VERSION 5.8 ;
BUSBITCHARS "[]" ;
DIVIDERCHAR "/" ;

SITE  CoreSite2
    CLASS       CORE ;
    SYMMETRY    Y ;
    SIZE        0.48 BY 7.56 ;
END  CoreSite2

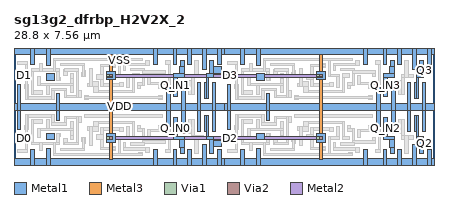
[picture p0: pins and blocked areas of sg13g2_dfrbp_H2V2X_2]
MACRO sg13g2_dfrbp_H2V2X_2
  CLASS CORE ;
  ORIGIN 0 0 ;
  FOREIGN sg13g2_dfrbp_H2V2X_2 0 0 ;
  SIZE 28.800 BY 7.560 ;
  SYMMETRY X Y ;
  SITE CoreSite2 ;
  PIN D0
    DIRECTION INPUT ;
    USE SIGNAL ;
    ANTENNAMODEL OXIDE1 ;
    ANTENNAGATEAREA 0.1092 LAYER Metal1 ;
    PORT
      LAYER Metal1 ;
        RECT 0.255 1.375 0.610 1.855 ;
    END
  END D0
  PIN Q0
    DIRECTION OUTPUT ;
    USE SIGNAL ;
    ANTENNADIFFAREA 0.7124 LAYER Metal1 ;
    PORT
      LAYER Metal1 ;
        RECT 13.440 0.595 13.700 1.775 ;
        RECT 13.440 1.045 14.210 1.490 ;
    END
    PORT
      LAYER Metal1 ;
        RECT 13.190 1.515 13.700 1.775 ;
        RECT 13.190 1.515 13.360 3.175 ;
        RECT 13.065 2.085 13.360 3.175 ;
    END
  END Q0
  PIN Q_N0
    DIRECTION OUTPUT ;
    USE SIGNAL ;
    ANTENNADIFFAREA 0.7068 LAYER Metal1 ;
    PORT
      LAYER Metal1 ;
        RECT 11.395 0.590 11.660 1.740 ;
        RECT 11.340 0.990 11.720 1.740 ;
        RECT 10.960 1.520 11.720 1.740 ;
        RECT 10.960 1.520 11.220 3.060 ;
    END
  END Q_N0
  PIN D1
    DIRECTION INPUT ;
    USE SIGNAL ;
    ANTENNAMODEL OXIDE1 ;
    ANTENNAGATEAREA 0.1092 LAYER Metal1 ;
    PORT
      LAYER Metal1 ;
        RECT 0.255 5.705 0.610 6.185 ;
    END
  END D1
  PIN Q1
    DIRECTION OUTPUT ;
    USE SIGNAL ;
    ANTENNADIFFAREA 0.7124 LAYER Metal1 ;
    PORT
      LAYER Metal1 ;
        RECT 13.065 4.385 13.360 5.475 ;
        RECT 13.190 4.385 13.360 6.045 ;
        RECT 13.190 5.785 13.700 6.045 ;
    END
    PORT
      LAYER Metal1 ;
        RECT 13.440 6.070 14.210 6.515 ;
        RECT 13.440 5.785 13.700 6.965 ;
    END
  END Q1
  PIN Q_N1
    DIRECTION OUTPUT ;
    USE SIGNAL ;
    ANTENNADIFFAREA 0.7068 LAYER Metal1 ;
    PORT
      LAYER Metal1 ;
        RECT 10.960 4.500 11.220 6.040 ;
        RECT 10.960 5.820 11.720 6.040 ;
        RECT 11.340 5.820 11.720 6.570 ;
        RECT 11.395 5.820 11.660 6.970 ;
    END
  END Q_N1
  PIN D2
    DIRECTION INPUT ;
    USE SIGNAL ;
    ANTENNAMODEL OXIDE1 ;
    ANTENNAGATEAREA 0.1092 LAYER Metal1 ;
    PORT
      LAYER Metal1 ;
        RECT 14.655 1.375 15.010 1.855 ;
    END
  END D2
  PIN Q2
    DIRECTION OUTPUT ;
    USE SIGNAL ;
    ANTENNADIFFAREA 0.7124 LAYER Metal1 ;
    PORT
      LAYER Metal1 ;
        RECT 27.840 0.595 28.100 1.775 ;
        RECT 27.840 1.045 28.610 1.490 ;
    END
    PORT
      LAYER Metal1 ;
        RECT 27.590 1.515 28.100 1.775 ;
        RECT 27.590 1.515 27.760 3.175 ;
        RECT 27.465 2.085 27.760 3.175 ;
    END
  END Q2
  PIN Q_N2
    DIRECTION OUTPUT ;
    USE SIGNAL ;
    ANTENNADIFFAREA 0.7068 LAYER Metal1 ;
    PORT
      LAYER Metal1 ;
        RECT 25.795 0.590 26.060 1.740 ;
        RECT 25.740 0.990 26.120 1.740 ;
        RECT 25.360 1.520 26.120 1.740 ;
        RECT 25.360 1.520 25.620 3.060 ;
    END
  END Q_N2
  PIN D3
    DIRECTION INPUT ;
    USE SIGNAL ;
    ANTENNAMODEL OXIDE1 ;
    ANTENNAGATEAREA 0.1092 LAYER Metal1 ;
    PORT
      LAYER Metal1 ;
        RECT 14.655 5.705 15.010 6.185 ;
    END
  END D3
  PIN Q3
    DIRECTION OUTPUT ;
    USE SIGNAL ;
    ANTENNADIFFAREA 0.7124 LAYER Metal1 ;
    PORT
      LAYER Metal1 ;
        RECT 27.465 4.385 27.760 5.475 ;
        RECT 27.590 4.385 27.760 6.045 ;
        RECT 27.590 5.785 28.100 6.045 ;
    END
    PORT
      LAYER Metal1 ;
        RECT 27.840 6.070 28.610 6.515 ;
        RECT 27.840 5.785 28.100 6.965 ;
    END
  END Q3
  PIN Q_N3
    DIRECTION OUTPUT ;
    USE SIGNAL ;
    ANTENNADIFFAREA 0.7068 LAYER Metal1 ;
    PORT
      LAYER Metal1 ;
        RECT 25.360 4.500 25.620 6.040 ;
        RECT 25.360 5.820 26.120 6.040 ;
        RECT 25.740 5.820 26.120 6.570 ;
        RECT 25.795 5.820 26.060 6.970 ;
    END
  END Q_N3
  PIN VDD
    DIRECTION INOUT ;
    USE POWER ;
    SHAPE ABUTMENT ;
    NETEXPR "VDD VDD!" ;
    PORT
      LAYER Metal1 ;
        RECT 11.470 1.980 11.730 4.000 ;
        RECT 25.870 1.980 26.130 4.000 ;
        RECT 13.580 2.085 13.840 4.000 ;
        RECT 12.555 2.085 12.815 4.000 ;
        RECT 27.980 2.085 28.240 4.000 ;
        RECT 26.955 2.085 27.215 4.000 ;
        RECT 0.215 2.215 0.470 4.000 ;
        RECT 14.615 2.215 14.870 4.000 ;
        RECT 10.450 2.460 10.710 4.000 ;
        RECT 24.850 2.460 25.110 4.000 ;
        RECT 2.945 2.860 3.115 4.000 ;
        RECT 17.345 2.860 17.515 4.000 ;
        RECT 0.000 3.560 14.400 4.000 ;
        RECT 14.400 3.560 28.800 4.000 ;
        RECT 2.945 3.560 3.115 4.700 ;
        RECT 17.345 3.560 17.515 4.700 ;
        RECT 10.450 3.560 10.710 5.100 ;
        RECT 24.850 3.560 25.110 5.100 ;
        RECT 0.215 3.560 0.470 5.345 ;
        RECT 14.615 3.560 14.870 5.345 ;
        RECT 13.580 3.560 13.840 5.475 ;
        RECT 12.555 3.560 12.815 5.475 ;
        RECT 27.980 3.560 28.240 5.475 ;
        RECT 26.955 3.560 27.215 5.475 ;
        RECT 11.470 3.560 11.730 5.580 ;
        RECT 25.870 3.560 26.130 5.580 ;
    END
  END VDD
  PIN VSS
    DIRECTION INOUT ;
    USE GROUND ;
    SHAPE ABUTMENT ;
    NETEXPR "VSS VSS!" ;
    PORT
      LAYER Metal1 ;
        RECT 0.000 -0.220 14.400 0.220 ;
        RECT 14.400 -0.220 28.800 0.220 ;
        RECT 13.935 -0.220 14.210 0.840 ;
        RECT 28.335 -0.220 28.610 0.840 ;
        RECT 11.910 -0.220 12.170 0.850 ;
        RECT 10.910 -0.220 11.150 0.850 ;
        RECT 26.310 -0.220 26.570 0.850 ;
        RECT 25.310 -0.220 25.550 0.850 ;
        RECT 9.560 -0.220 9.820 0.885 ;
        RECT 1.140 -0.220 1.400 0.885 ;
        RECT 23.960 -0.220 24.220 0.885 ;
        RECT 15.540 -0.220 15.800 0.885 ;
        RECT 2.235 -0.220 2.495 0.915 ;
        RECT 16.635 -0.220 16.895 0.915 ;
        RECT 12.930 -0.220 13.190 1.210 ;
        RECT 27.330 -0.220 27.590 1.210 ;
    END
    PORT
      LAYER Metal1 ;
        RECT 12.930 6.350 13.190 7.780 ;
        RECT 27.330 6.350 27.590 7.780 ;
        RECT 2.235 6.645 2.495 7.780 ;
        RECT 16.635 6.645 16.895 7.780 ;
        RECT 9.560 6.675 9.820 7.780 ;
        RECT 1.140 6.675 1.400 7.780 ;
        RECT 23.960 6.675 24.220 7.780 ;
        RECT 15.540 6.675 15.800 7.780 ;
        RECT 11.910 6.710 12.170 7.780 ;
        RECT 10.910 6.710 11.150 7.780 ;
        RECT 26.310 6.710 26.570 7.780 ;
        RECT 25.310 6.710 25.550 7.780 ;
        RECT 13.935 6.720 14.210 7.780 ;
        RECT 28.335 6.720 28.610 7.780 ;
        RECT 0.000 7.340 14.400 7.780 ;
        RECT 14.400 7.340 28.800 7.780 ;
    END
  END VSS
  PIN CLK
    DIRECTION INPUT ;
    USE SIGNAL ;
    ANTENNAMODEL OXIDE1 ;
    ANTENNAGATEAREA 0.2418 LAYER Metal1 ;
    PORT
      LAYER Metal1 ;
        RECT 6.365 1.335 6.990 1.935 ;
        RECT 6.365 5.625 6.990 6.225 ;
        RECT 20.765 1.335 21.390 1.935 ;
        RECT 20.765 5.625 21.390 6.225 ;
      LAYER Metal3 ;
        RECT 6.580 0.200 6.780 7.360 ;
      LAYER Via1 ;
        RECT 6.365 1.540 6.555 1.730 ;
      LAYER Via2 ;
        RECT 6.580 1.540 6.770 1.730 ;
      LAYER Metal2 ;
        RECT 6.360 1.535 6.775 1.735 ;
      LAYER Via1 ;
        RECT 6.365 5.830 6.555 6.020 ;
      LAYER Via2 ;
        RECT 6.580 5.830 6.770 6.020 ;
      LAYER Metal2 ;
        RECT 6.360 5.825 6.775 6.025 ;
      LAYER Metal3 ;
        RECT 20.980 0.200 21.180 7.360 ;
      LAYER Via1 ;
        RECT 20.765 1.540 20.955 1.730 ;
      LAYER Via2 ;
        RECT 20.980 1.540 21.170 1.730 ;
      LAYER Metal2 ;
        RECT 20.760 1.535 21.175 1.735 ;
      LAYER Via1 ;
        RECT 20.765 5.830 20.955 6.020 ;
      LAYER Via2 ;
        RECT 20.980 5.830 21.170 6.020 ;
      LAYER Metal2 ;
        RECT 20.760 5.825 21.175 6.025 ;
        RECT 6.360 1.535 21.175 1.735 ;
        RECT 6.360 5.825 21.175 6.025 ;
    END
  END CLK
  PIN RESET_B
    DIRECTION INPUT ;
    USE SIGNAL ;
    ANTENNAPARTIALMETALAREA 0.905 LAYER Metal1 ;
    ANTENNAMODEL OXIDE1 ;
    ANTENNAGATEAREA 0.3276 LAYER Metal1 ;
    ANTENNAMAXAREACAR 2.762515 LAYER Metal1 ;
    PORT
      LAYER Metal1 ;
        RECT 2.200 1.510 2.750 1.965 ;
        RECT 16.600 1.510 17.150 1.965 ;
    END
    PORT
      LAYER Metal1 ;
        RECT 2.200 5.595 2.750 6.050 ;
        RECT 16.600 5.595 17.150 6.050 ;
    END
  END RESET_B
  OBS
    LAYER Metal1 ;
      RECT 11.980 1.980 12.360 2.920 ;
      RECT 12.190 1.535 12.360 2.920 ;
      RECT 12.190 1.535 12.985 1.795 ;
      RECT 12.400 0.590 12.685 1.795 ;
      RECT 9.910 2.100 10.170 2.495 ;
      RECT 9.130 2.100 10.730 2.260 ;
      RECT 10.570 0.625 10.730 2.260 ;
      RECT 9.130 1.655 9.385 2.260 ;
      RECT 10.380 0.625 10.730 0.885 ;
      RECT 8.455 2.125 8.660 2.500 ;
      RECT 8.455 2.125 8.950 2.295 ;
      RECT 8.790 1.145 8.950 2.295 ;
      RECT 10.165 1.275 10.390 1.665 ;
      RECT 8.790 1.275 10.390 1.465 ;
      RECT 7.960 1.145 8.970 1.315 ;
      RECT 9.910 3.025 10.180 3.285 ;
      RECT 4.855 3.025 5.115 3.285 ;
      RECT 4.855 3.075 10.180 3.235 ;
      RECT 7.510 0.805 7.680 1.310 ;
      RECT 7.510 0.805 9.310 0.965 ;
      RECT 9.050 0.625 9.310 0.965 ;
      RECT 1.200 2.640 1.940 2.900 ;
      RECT 1.200 1.170 1.360 2.900 ;
      RECT 7.745 1.555 7.935 2.450 ;
      RECT 2.935 1.755 3.215 1.965 ;
      RECT 2.935 1.170 3.095 1.965 ;
      RECT 7.170 1.555 7.935 1.725 ;
      RECT 7.170 0.440 7.330 1.725 ;
      RECT 1.200 1.170 3.095 1.330 ;
      RECT 2.705 0.440 2.875 1.330 ;
      RECT 1.720 0.815 1.980 1.330 ;
      RECT 8.540 0.440 8.800 0.625 ;
      RECT 2.705 0.440 8.800 0.605 ;
      RECT 5.425 2.630 8.275 2.790 ;
      RECT 8.115 1.510 8.275 2.790 ;
      RECT 5.425 2.060 5.785 2.790 ;
      RECT 5.020 2.150 5.785 2.410 ;
      RECT 5.155 2.060 5.785 2.410 ;
      RECT 5.155 1.135 5.415 2.410 ;
      RECT 8.115 1.510 8.600 1.770 ;
      RECT 5.965 2.145 7.525 2.370 ;
      RECT 7.265 2.075 7.525 2.370 ;
      RECT 5.965 0.855 6.125 2.370 ;
      RECT 5.650 1.540 6.125 1.870 ;
      RECT 6.755 0.810 6.990 1.070 ;
      RECT 5.965 0.855 6.990 1.025 ;
      RECT 4.630 1.440 4.895 1.700 ;
      RECT 4.685 1.300 4.895 1.700 ;
      RECT 4.685 0.785 4.865 1.700 ;
      RECT 3.165 0.785 4.865 0.960 ;
      RECT 0.790 3.080 2.765 3.240 ;
      RECT 2.605 2.520 2.765 3.240 ;
      RECT 3.455 2.985 4.625 3.145 ;
      RECT 4.290 2.685 4.625 3.145 ;
      RECT 0.790 2.240 0.980 3.240 ;
      RECT 3.455 2.520 3.615 3.145 ;
      RECT 4.290 1.170 4.450 3.145 ;
      RECT 2.605 2.520 3.615 2.680 ;
      RECT 0.720 2.240 0.980 2.520 ;
      RECT 0.790 0.645 0.950 3.240 ;
      RECT 3.385 1.225 3.645 1.640 ;
      RECT 3.465 1.170 4.450 1.330 ;
      RECT 0.210 0.645 0.950 0.840 ;
      RECT 2.245 2.145 2.425 2.900 ;
      RECT 3.890 1.510 4.075 2.805 ;
      RECT 2.245 2.145 4.075 2.315 ;
      RECT 1.585 2.145 4.075 2.305 ;
      RECT 1.585 1.705 1.845 2.305 ;
      RECT 3.890 1.510 4.110 1.810 ;
      RECT 11.980 4.640 12.360 5.580 ;
      RECT 12.190 4.640 12.360 6.025 ;
      RECT 12.190 5.765 12.985 6.025 ;
      RECT 12.400 5.765 12.685 6.970 ;
      RECT 9.910 5.065 10.170 5.460 ;
      RECT 9.130 5.300 10.730 5.460 ;
      RECT 10.570 5.300 10.730 6.935 ;
      RECT 9.130 5.300 9.385 5.905 ;
      RECT 10.380 6.675 10.730 6.935 ;
      RECT 8.455 5.060 8.660 5.435 ;
      RECT 8.455 5.265 8.950 5.435 ;
      RECT 8.790 5.265 8.950 6.415 ;
      RECT 10.165 5.895 10.390 6.285 ;
      RECT 8.790 6.095 10.390 6.285 ;
      RECT 7.960 6.245 8.970 6.415 ;
      RECT 9.910 4.275 10.180 4.535 ;
      RECT 4.855 4.275 5.115 4.535 ;
      RECT 4.855 4.325 10.180 4.485 ;
      RECT 7.510 6.250 7.680 6.755 ;
      RECT 7.510 6.595 9.310 6.755 ;
      RECT 9.050 6.595 9.310 6.935 ;
      RECT 1.200 4.660 1.940 4.920 ;
      RECT 1.200 4.660 1.360 6.390 ;
      RECT 7.745 5.110 7.935 6.005 ;
      RECT 2.935 5.595 3.215 5.805 ;
      RECT 2.935 5.595 3.095 6.390 ;
      RECT 7.170 5.835 7.935 6.005 ;
      RECT 7.170 5.835 7.330 7.120 ;
      RECT 1.200 6.230 3.095 6.390 ;
      RECT 2.705 6.230 2.875 7.120 ;
      RECT 1.720 6.230 1.980 6.745 ;
      RECT 8.540 6.935 8.800 7.120 ;
      RECT 2.705 6.955 8.800 7.120 ;
      RECT 5.425 4.770 8.275 4.930 ;
      RECT 8.115 4.770 8.275 6.050 ;
      RECT 5.425 4.770 5.785 5.500 ;
      RECT 5.020 5.150 5.785 5.410 ;
      RECT 5.155 5.150 5.785 5.500 ;
      RECT 5.155 5.150 5.415 6.425 ;
      RECT 8.115 5.790 8.600 6.050 ;
      RECT 5.965 5.190 7.525 5.415 ;
      RECT 7.265 5.190 7.525 5.485 ;
      RECT 5.965 5.190 6.125 6.705 ;
      RECT 5.650 5.690 6.125 6.020 ;
      RECT 6.755 6.490 6.990 6.750 ;
      RECT 5.965 6.535 6.990 6.705 ;
      RECT 4.630 5.860 4.895 6.120 ;
      RECT 4.685 5.860 4.895 6.260 ;
      RECT 4.685 5.860 4.865 6.775 ;
      RECT 3.165 6.600 4.865 6.775 ;
      RECT 0.790 4.320 2.765 4.480 ;
      RECT 2.605 4.320 2.765 5.040 ;
      RECT 3.455 4.415 4.625 4.575 ;
      RECT 4.290 4.415 4.625 4.875 ;
      RECT 0.790 4.320 0.980 5.320 ;
      RECT 3.455 4.415 3.615 5.040 ;
      RECT 4.290 4.415 4.450 6.390 ;
      RECT 2.605 4.880 3.615 5.040 ;
      RECT 0.720 5.040 0.980 5.320 ;
      RECT 0.790 4.320 0.950 6.915 ;
      RECT 3.385 5.920 3.645 6.335 ;
      RECT 3.465 6.230 4.450 6.390 ;
      RECT 0.210 6.720 0.950 6.915 ;
      RECT 2.245 4.660 2.425 5.415 ;
      RECT 3.890 4.755 4.075 6.050 ;
      RECT 2.245 5.245 4.075 5.415 ;
      RECT 1.585 5.255 4.075 5.415 ;
      RECT 1.585 5.255 1.845 5.855 ;
      RECT 3.890 5.750 4.110 6.050 ;
      RECT 26.380 1.980 26.760 2.920 ;
      RECT 26.590 1.535 26.760 2.920 ;
      RECT 26.590 1.535 27.385 1.795 ;
      RECT 26.800 0.590 27.085 1.795 ;
      RECT 24.310 2.100 24.570 2.495 ;
      RECT 23.530 2.100 25.130 2.260 ;
      RECT 24.970 0.625 25.130 2.260 ;
      RECT 23.530 1.655 23.785 2.260 ;
      RECT 24.780 0.625 25.130 0.885 ;
      RECT 22.855 2.125 23.060 2.500 ;
      RECT 22.855 2.125 23.350 2.295 ;
      RECT 23.190 1.145 23.350 2.295 ;
      RECT 24.565 1.275 24.790 1.665 ;
      RECT 23.190 1.275 24.790 1.465 ;
      RECT 22.360 1.145 23.370 1.315 ;
      RECT 24.310 3.025 24.580 3.285 ;
      RECT 19.255 3.025 19.515 3.285 ;
      RECT 19.255 3.075 24.580 3.235 ;
      RECT 21.910 0.805 22.080 1.310 ;
      RECT 21.910 0.805 23.710 0.965 ;
      RECT 23.450 0.625 23.710 0.965 ;
      RECT 15.600 2.640 16.340 2.900 ;
      RECT 15.600 1.170 15.760 2.900 ;
      RECT 22.145 1.555 22.335 2.450 ;
      RECT 17.335 1.755 17.615 1.965 ;
      RECT 17.335 1.170 17.495 1.965 ;
      RECT 21.570 1.555 22.335 1.725 ;
      RECT 21.570 0.440 21.730 1.725 ;
      RECT 15.600 1.170 17.495 1.330 ;
      RECT 17.105 0.440 17.275 1.330 ;
      RECT 16.120 0.815 16.380 1.330 ;
      RECT 22.940 0.440 23.200 0.625 ;
      RECT 17.105 0.440 23.200 0.605 ;
      RECT 19.825 2.630 22.675 2.790 ;
      RECT 22.515 1.510 22.675 2.790 ;
      RECT 19.825 2.060 20.185 2.790 ;
      RECT 19.420 2.150 20.185 2.410 ;
      RECT 19.555 2.060 20.185 2.410 ;
      RECT 19.555 1.135 19.815 2.410 ;
      RECT 22.515 1.510 23.000 1.770 ;
      RECT 20.365 2.145 21.925 2.370 ;
      RECT 21.665 2.075 21.925 2.370 ;
      RECT 20.365 0.855 20.525 2.370 ;
      RECT 20.050 1.540 20.525 1.870 ;
      RECT 21.155 0.810 21.390 1.070 ;
      RECT 20.365 0.855 21.390 1.025 ;
      RECT 19.030 1.440 19.295 1.700 ;
      RECT 19.085 1.300 19.295 1.700 ;
      RECT 19.085 0.785 19.265 1.700 ;
      RECT 17.565 0.785 19.265 0.960 ;
      RECT 15.190 3.080 17.165 3.240 ;
      RECT 17.005 2.520 17.165 3.240 ;
      RECT 17.855 2.985 19.025 3.145 ;
      RECT 18.690 2.685 19.025 3.145 ;
      RECT 15.190 2.240 15.380 3.240 ;
      RECT 17.855 2.520 18.015 3.145 ;
      RECT 18.690 1.170 18.850 3.145 ;
      RECT 17.005 2.520 18.015 2.680 ;
      RECT 15.120 2.240 15.380 2.520 ;
      RECT 15.190 0.645 15.350 3.240 ;
      RECT 17.785 1.225 18.045 1.640 ;
      RECT 17.865 1.170 18.850 1.330 ;
      RECT 14.610 0.645 15.350 0.840 ;
      RECT 16.645 2.145 16.825 2.900 ;
      RECT 18.290 1.510 18.475 2.805 ;
      RECT 16.645 2.145 18.475 2.315 ;
      RECT 15.985 2.145 18.475 2.305 ;
      RECT 15.985 1.705 16.245 2.305 ;
      RECT 18.290 1.510 18.510 1.810 ;
      RECT 26.380 4.640 26.760 5.580 ;
      RECT 26.590 4.640 26.760 6.025 ;
      RECT 26.590 5.765 27.385 6.025 ;
      RECT 26.800 5.765 27.085 6.970 ;
      RECT 24.310 5.065 24.570 5.460 ;
      RECT 23.530 5.300 25.130 5.460 ;
      RECT 24.970 5.300 25.130 6.935 ;
      RECT 23.530 5.300 23.785 5.905 ;
      RECT 24.780 6.675 25.130 6.935 ;
      RECT 22.855 5.060 23.060 5.435 ;
      RECT 22.855 5.265 23.350 5.435 ;
      RECT 23.190 5.265 23.350 6.415 ;
      RECT 24.565 5.895 24.790 6.285 ;
      RECT 23.190 6.095 24.790 6.285 ;
      RECT 22.360 6.245 23.370 6.415 ;
      RECT 24.310 4.275 24.580 4.535 ;
      RECT 19.255 4.275 19.515 4.535 ;
      RECT 19.255 4.325 24.580 4.485 ;
      RECT 21.910 6.250 22.080 6.755 ;
      RECT 21.910 6.595 23.710 6.755 ;
      RECT 23.450 6.595 23.710 6.935 ;
      RECT 15.600 4.660 16.340 4.920 ;
      RECT 15.600 4.660 15.760 6.390 ;
      RECT 22.145 5.110 22.335 6.005 ;
      RECT 17.335 5.595 17.615 5.805 ;
      RECT 17.335 5.595 17.495 6.390 ;
      RECT 21.570 5.835 22.335 6.005 ;
      RECT 21.570 5.835 21.730 7.120 ;
      RECT 15.600 6.230 17.495 6.390 ;
      RECT 17.105 6.230 17.275 7.120 ;
      RECT 16.120 6.230 16.380 6.745 ;
      RECT 22.940 6.935 23.200 7.120 ;
      RECT 17.105 6.955 23.200 7.120 ;
      RECT 19.825 4.770 22.675 4.930 ;
      RECT 22.515 4.770 22.675 6.050 ;
      RECT 19.825 4.770 20.185 5.500 ;
      RECT 19.420 5.150 20.185 5.410 ;
      RECT 19.555 5.150 20.185 5.500 ;
      RECT 19.555 5.150 19.815 6.425 ;
      RECT 22.515 5.790 23.000 6.050 ;
      RECT 20.365 5.190 21.925 5.415 ;
      RECT 21.665 5.190 21.925 5.485 ;
      RECT 20.365 5.190 20.525 6.705 ;
      RECT 20.050 5.690 20.525 6.020 ;
      RECT 21.155 6.490 21.390 6.750 ;
      RECT 20.365 6.535 21.390 6.705 ;
      RECT 19.030 5.860 19.295 6.120 ;
      RECT 19.085 5.860 19.295 6.260 ;
      RECT 19.085 5.860 19.265 6.775 ;
      RECT 17.565 6.600 19.265 6.775 ;
      RECT 15.190 4.320 17.165 4.480 ;
      RECT 17.005 4.320 17.165 5.040 ;
      RECT 17.855 4.415 19.025 4.575 ;
      RECT 18.690 4.415 19.025 4.875 ;
      RECT 15.190 4.320 15.380 5.320 ;
      RECT 17.855 4.415 18.015 5.040 ;
      RECT 18.690 4.415 18.850 6.390 ;
      RECT 17.005 4.880 18.015 5.040 ;
      RECT 15.120 5.040 15.380 5.320 ;
      RECT 15.190 4.320 15.350 6.915 ;
      RECT 17.785 5.920 18.045 6.335 ;
      RECT 17.865 6.230 18.850 6.390 ;
      RECT 14.610 6.720 15.350 6.915 ;
      RECT 16.645 4.660 16.825 5.415 ;
      RECT 18.290 4.755 18.475 6.050 ;
      RECT 16.645 5.245 18.475 5.415 ;
      RECT 15.985 5.255 18.475 5.415 ;
      RECT 15.985 5.255 16.245 5.855 ;
      RECT 18.290 5.750 18.510 6.050 ;
  END
END sg13g2_dfrbp_H2V2X_2

END LIBRARY
